VERSION 5.8 ;
DIVIDERCHAR "/" ;
BUSBITCHARS "[]" ;
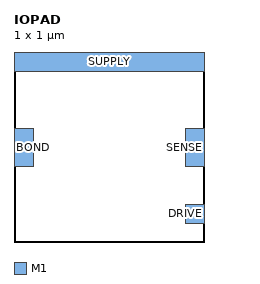
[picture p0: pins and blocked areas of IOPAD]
MACRO IOPAD
  CLASS PAD INOUT ;
  ORIGIN 0 0 ;
  SIZE 1 BY 1 ;
  SYMMETRY X Y ;
  PIN BOND
    DIRECTION INOUT ;
    USE SIGNAL ;
    PORT
      LAYER M1 ;
        RECT 0.00 0.40 0.10 0.60 ;
    END
  END BOND
  PIN DRIVE
    DIRECTION INPUT ;
    USE SIGNAL ;
    PORT
      LAYER M1 ;
        RECT 0.90 0.10 1.00 0.20 ;
    END
  END DRIVE
  PIN SENSE
    DIRECTION OUTPUT ;
    USE SIGNAL ;
    PORT
      LAYER M1 ;
        RECT 0.90 0.40 1.00 0.60 ;
    END
  END SENSE
  PIN SUPPLY
    DIRECTION INOUT ;
    USE POWER ;
    PORT
      LAYER M1 ;
        RECT 0.00 0.90 1.00 1.00 ;
    END
  END SUPPLY
END IOPAD
END LIBRARY
